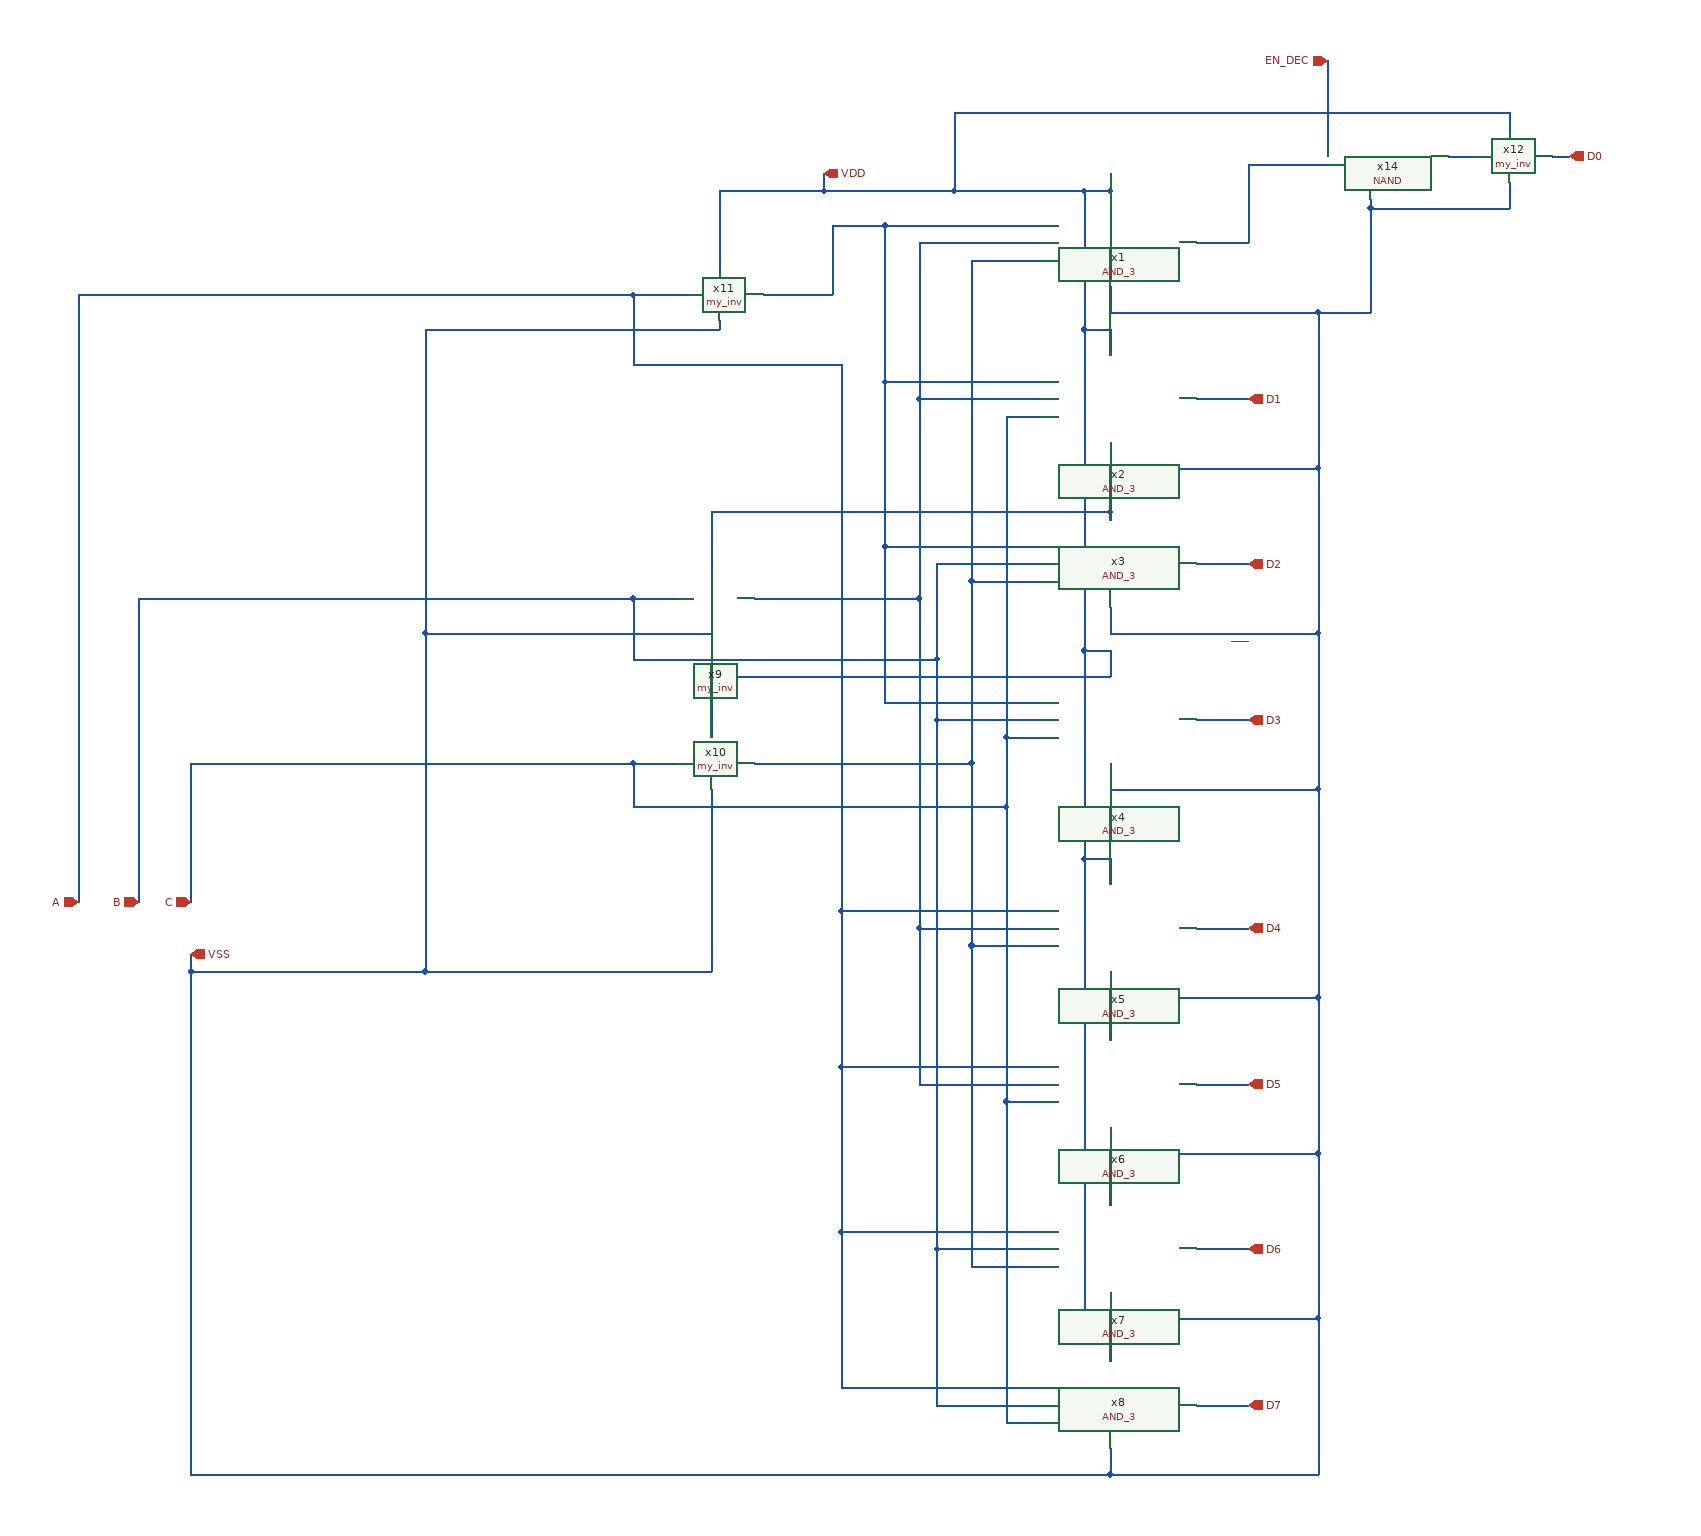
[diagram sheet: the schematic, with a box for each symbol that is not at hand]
v {xschem version=3.4.6 file_version=1.2}
G {}
K {}
V {}
S {}
E {}
L 4 130 0 150 0 {}
N -10 -520 -10 -510 {lab=VDD}
N -10 -360 -10 -330 {lab=VDD}
N -10 -230 -10 -200 {lab=VSS}
N -10 -410 -10 -380 {lab=VSS}
N -10 -150 -10 -140 {lab=VDD}
N -10 10 -10 40 {lab=VDD}
N -10 140 -10 170 {lab=VSS}
N -10 -40 -10 -10 {lab=VSS}
N -10 250 -10 280 {lab=VDD}
N -10 430 -10 460 {lab=VDD}
N -10 560 -10 590 {lab=VSS}
N -10 380 -10 410 {lab=VSS}
N -10 620 -10 650 {lab=VDD}
N -10 800 -10 830 {lab=VDD}
N -10 930 -10 960 {lab=VSS}
N -10 750 -10 780 {lab=VSS}
N 90 -460 150 -460 {lab=#net1}
N 90 -90 150 -90 {lab=D2}
N 90 90 150 90 {lab=D3}
N 90 330 150 330 {lab=D4}
N 90 -280 150 -280 {lab=D1}
N 90 510 150 510 {lab=D5}
N 90 700 150 700 {lab=D6}
N 90 880 150 880 {lab=D7}
N -1200 -400 -1200 300 {lab=A}
N -560 -400 -500 -400 {lab=A}
N -1130 -50 -1130 300 {lab=B}
N -1070 140 -1070 300 {lab=C}
N -330 -480 -330 -400 {lab=#net2}
N -270 -480 -90 -480 {lab=#net2}
N -330 -480 -270 -480 {lab=#net2}
N -270 -480 -270 -300 {lab=#net2}
N -270 -300 -90 -300 {lab=#net2}
N -270 -300 -270 -110 {lab=#net2}
N -270 -110 -90 -110 {lab=#net2}
N -270 -110 -270 70 {lab=#net2}
N -270 70 -90 70 {lab=#net2}
N -560 -400 -560 -320 {lab=A}
N -1200 -400 -560 -400 {lab=A}
N -560 -320 -320 -320 {lab=A}
N -320 310 -90 310 {lab=A}
N -320 310 -320 490 {lab=A}
N -320 490 -90 490 {lab=A}
N -320 490 -320 680 {lab=A}
N -320 680 -90 680 {lab=A}
N -320 680 -320 860 {lab=A}
N -320 860 -90 860 {lab=A}
N -230 -280 -230 -50 {lab=#net3}
N -230 -460 -90 -460 {lab=#net3}
N -230 -280 -90 -280 {lab=#net3}
N -230 -460 -230 -280 {lab=#net3}
N -230 -50 -230 330 {lab=#net3}
N -230 330 -90 330 {lab=#net3}
N -230 330 -230 510 {lab=#net3}
N -230 510 -90 510 {lab=#net3}
N -560 -50 -560 20 {lab=B}
N -1130 -50 -560 -50 {lab=B}
N -560 20 -210 20 {lab=B}
N -210 -90 -210 20 {lab=B}
N -210 -90 -90 -90 {lab=B}
N -210 20 -210 90 {lab=B}
N -210 90 -90 90 {lab=B}
N -210 90 -210 700 {lab=B}
N -210 700 -90 700 {lab=B}
N -210 700 -210 880 {lab=B}
N -210 880 -90 880 {lab=B}
N -170 -70 -170 140 {lab=#net4}
N -170 -440 -90 -440 {lab=#net4}
N -170 -70 -90 -70 {lab=#net4}
N -170 -440 -170 -70 {lab=#net4}
N -170 140 -170 350 {lab=#net4}
N -170 350 -90 350 {lab=#net4}
N -170 350 -170 720 {lab=#net4}
N -170 720 -90 720 {lab=#net4}
N -130 110 -130 190 {lab=C}
N -130 110 -90 110 {lab=C}
N -130 -260 -130 110 {lab=C}
N -130 -260 -90 -260 {lab=C}
N -130 190 -130 530 {lab=C}
N -130 530 -90 530 {lab=C}
N -130 530 -130 900 {lab=C}
N -130 900 -90 900 {lab=C}
N -10 780 230 780 {lab=VSS}
N 230 780 230 960 {lab=VSS}
N -10 960 230 960 {lab=VSS}
N 230 590 230 780 {lab=VSS}
N -10 -200 230 -200 {lab=VSS}
N 230 -380 230 -200 {lab=VSS}
N -10 -10 230 -10 {lab=VSS}
N 230 -200 230 -10 {lab=VSS}
N -10 170 230 170 {lab=VSS}
N 230 -10 230 170 {lab=VSS}
N -10 410 230 410 {lab=VSS}
N 230 170 230 410 {lab=VSS}
N -10 590 230 590 {lab=VSS}
N 230 410 230 590 {lab=VSS}
N -1070 960 -10 960 {lab=VSS}
N -560 -50 -510 -50 {lab=B}
N -560 190 -130 190 {lab=C}
N -560 140 -560 190 {lab=C}
N -560 140 -510 140 {lab=C}
N -1070 140 -560 140 {lab=C}
N -320 -320 -320 310 {lab=A}
N -800 380 -470 380 {lab=VSS}
N -1070 360 -1070 380 {lab=VSS}
N -800 -10 -470 -10 {lab=VSS}
N -1070 380 -800 380 {lab=VSS}
N -800 -360 -460 -360 {lab=VSS}
N -800 -10 -800 380 {lab=VSS}
N -800 -360 -800 -10 {lab=VSS}
N -460 -520 -460 -430 {lab=VDD}
N -40 -520 -10 -520 {lab=VDD}
N -10 -540 -10 -520 {lab=VDD}
N -470 -150 -470 -80 {lab=VDD}
N -470 -150 -10 -150 {lab=VDD}
N -10 -170 -10 -150 {lab=VDD}
N -470 40 -470 110 {lab=VDD}
N -470 40 -10 40 {lab=VDD}
N -40 800 -10 800 {lab=VDD}
N -40 620 -40 800 {lab=VDD}
N -190 -520 -40 -520 {lab=VDD}
N -40 620 -10 620 {lab=VDD}
N -40 430 -40 620 {lab=VDD}
N -40 430 -10 430 {lab=VDD}
N -40 250 -40 430 {lab=VDD}
N -40 250 -10 250 {lab=VDD}
N -40 10 -40 250 {lab=VDD}
N -40 10 -10 10 {lab=VDD}
N -40 -170 -40 10 {lab=VDD}
N -40 -170 -10 -170 {lab=VDD}
N -40 -360 -40 -170 {lab=VDD}
N -40 -360 -10 -360 {lab=VDD}
N -40 -520 -40 -360 {lab=VDD}
N -1070 380 -1070 960 {lab=VSS}
N -460 -370 -460 -360 {lab=VSS}
N -470 -20 -470 -10 {lab=VSS}
N -420 -50 -230 -50 {lab=#net3}
N -470 170 -470 380 {lab=VSS}
N -420 140 -170 140 {lab=#net4}
N -410 -400 -330 -400 {lab=#net2}
N 380 -560 410 -560 {lab=#net5}
N 150 -550 150 -460 {lab=#net1}
N 150 -550 240 -550 {lab=#net1}
N -190 -610 450 -610 {lab=VDD}
N -190 -610 -190 -520 {lab=VDD}
N -340 -520 -190 -520 {lab=VDD}
N 290 -500 290 -380 {lab=VSS}
N 230 -380 290 -380 {lab=VSS}
N -10 -380 230 -380 {lab=VSS}
N 240 -670 240 -570 {lab=EN_DEC}
N 450 -610 450 -590 {lab=VDD}
N 290 -500 450 -500 {lab=VSS}
N 290 -510 290 -500 {lab=VSS}
N 450 -530 450 -500 {lab=VSS}
N 500 -560 520 -560 {lab=D0}
N -340 -540 -340 -520 {lab=VDD}
N -460 -520 -340 -520 {lab=VDD}
C {opin.sym} 520 -560 0 0 {name=p1 lab=D0
}
C {ipin.sym} -1200 300 0 0 {name=p8 lab=A}
C {iopin.sym} -340 -540 1 1 {name=p9 lab=VDD}
C {iopin.sym} -1070 360 0 1 {name=p10 lab=VSS}
C {ipin.sym} -1130 300 0 0 {name=p6 lab=B}
C {ipin.sym} -1070 300 0 0 {name=p13 lab=C}
C {opin.sym} 150 -280 0 0 {name=p2 lab=D1
}
C {opin.sym} 150 -90 0 0 {name=p3 lab=D2
}
C {opin.sym} 150 90 0 0 {name=p4 lab=D3
}
C {opin.sym} 150 330 0 0 {name=p5 lab=D4
}
C {opin.sym} 150 510 0 0 {name=p14 lab=D5
}
C {opin.sym} 150 700 0 0 {name=p17 lab=D6
}
C {opin.sym} 150 880 0 0 {name=p18 lab=D7
}
C {AND_3.sym} -110 -380 0 0 {name=x1}
C {AND_3.sym} -110 -200 0 0 {name=x2}
C {AND_3.sym} -110 -10 0 0 {name=x3}
C {AND_3.sym} -110 170 0 0 {name=x4}
C {AND_3.sym} -110 410 0 0 {name=x5}
C {AND_3.sym} -110 590 0 0 {name=x6}
C {AND_3.sym} -110 780 0 0 {name=x7}
C {AND_3.sym} -110 960 0 0 {name=x8}
C {NAND.sym} 360 -470 0 0 {name=x14}
C {my_inv.sym} -450 -330 0 0 {name=x11}
C {my_inv.sym} -460 20 0 0 {name=x9}
C {my_inv.sym} -460 210 0 0 {name=x10}
C {my_inv.sym} 460 -490 0 0 {name=x12}
C {ipin.sym} 240 -670 0 0 {name=p7 lab=EN_DEC}
